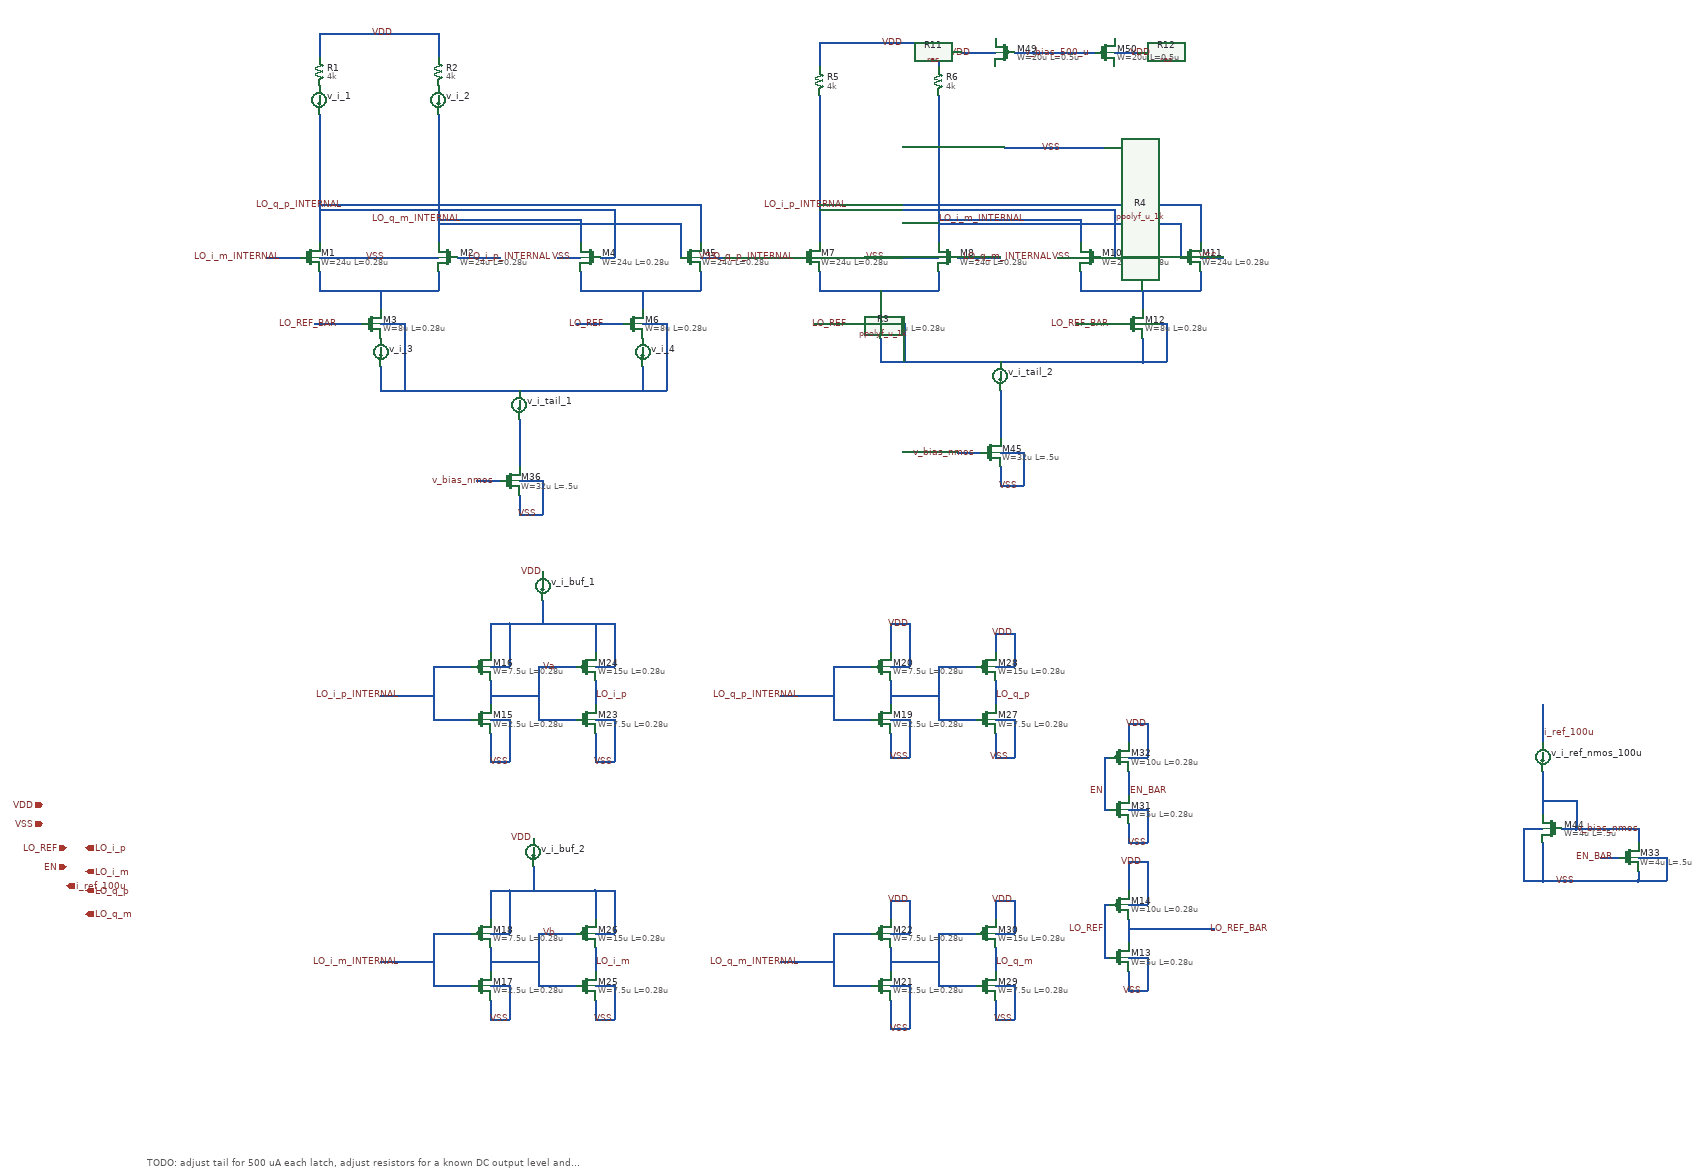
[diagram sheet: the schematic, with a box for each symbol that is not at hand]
v {xschem version=3.4.8RC file_version=1.3}
G {}
K {}
V {}
S {}
F {}
E {}
T {TODO: adjust tail for 500 uA each latch, adjust resistors for a known DC output level and swing, add latch output stage to couple into output buffer. Remove self biasing or add wideband buffer to help with low frequency clock signasl} 50 170 0 0 0.2 0.2 {}
N 410 -1690 410 -1650 {lab=#net1}
N 410 -1650 660 -1650 {lab=#net1}
N 660 -1690 660 -1650 {lab=#net1}
N 540 -1650 540 -1610 {lab=#net1}
N 400 -1580 500 -1580 {lab=LO_REF_BAR}
N 540 -1490 540 -1440 {lab=#net2}
N 300 -1720 370 -1720 {lab=LO_i_m_INTERNAL}
N 700 -1720 790 -1720 {lab=LO_i_p_INTERNAL}
N 660 -1860 660 -1750 {lab=LO_q_m_INTERNAL}
N 410 -1870 410 -1750 {lab=LO_q_p_INTERNAL}
N 410 -2190 660 -2190 {lab=VDD}
N 960 -1690 960 -1650 {lab=#net3}
N 960 -1650 1210 -1650 {lab=#net3}
N 1210 -1690 1210 -1650 {lab=#net3}
N 1090 -1650 1090 -1610 {lab=#net3}
N 950 -1580 1050 -1580 {lab=LO_REF}
N 1090 -1490 1090 -1440 {lab=#net2}
N 960 -1800 960 -1750 {lab=LO_q_m_INTERNAL}
N 1000 -1720 1030 -1720 {lab=LO_q_p_INTERNAL}
N 1030 -1770 1030 -1720 {lab=LO_q_p_INTERNAL}
N 660 -1800 960 -1800 {lab=LO_q_m_INTERNAL}
N 1030 -1820 1030 -1770 {lab=LO_q_p_INTERNAL}
N 410 -1820 1030 -1820 {lab=LO_q_p_INTERNAL}
N 1170 -1790 1170 -1720 {lab=LO_q_m_INTERNAL}
N 660 -1790 1170 -1790 {lab=LO_q_m_INTERNAL}
N 1210 -1830 1210 -1750 {lab=LO_q_p_INTERNAL}
N 410 -1830 1210 -1830 {lab=LO_q_p_INTERNAL}
N 540 -1440 1090 -1440 {lab=#net2}
N 540 -1580 590 -1580 {lab=#net2}
N 590 -1510 590 -1440 {lab=#net2}
N 590 -1580 590 -1570 {lab=#net2}
N 1090 -1580 1140 -1580 {lab=#net2}
N 1140 -1520 1140 -1440 {lab=#net2}
N 1090 -1440 1140 -1440 {lab=#net2}
N 910 -1720 960 -1720 {lab=VSS}
N 1210 -1720 1260 -1720 {lab=VSS}
N 410 -1720 660 -1720 {lab=VSS}
N 1460 -1690 1460 -1650 {lab=#net4}
N 1460 -1650 1710 -1650 {lab=#net4}
N 1710 -1690 1710 -1650 {lab=#net4}
N 1590 -1650 1590 -1610 {lab=#net4}
N 1450 -1580 1550 -1580 {lab=LO_REF}
N 1590 -1550 1590 -1500 {lab=#net5}
N 1350 -1720 1420 -1720 {lab=LO_q_p_INTERNAL}
N 1750 -1720 1840 -1720 {lab=LO_q_m_INTERNAL}
N 1710 -1860 1710 -1750 {lab=LO_i_m_INTERNAL}
N 1460 -1870 1460 -1750 {lab=LO_i_p_INTERNAL}
N 1460 -2170 1710 -2170 {lab=VDD}
N 2010 -1690 2010 -1650 {lab=#net6}
N 2010 -1650 2260 -1650 {lab=#net6}
N 2260 -1690 2260 -1650 {lab=#net6}
N 2140 -1650 2140 -1610 {lab=#net6}
N 2000 -1580 2100 -1580 {lab=LO_REF_BAR}
N 2140 -1550 2140 -1500 {lab=#net5}
N 2010 -1800 2010 -1750 {lab=LO_i_m_INTERNAL}
N 2050 -1720 2080 -1720 {lab=LO_i_p_INTERNAL}
N 2080 -1770 2080 -1720 {lab=LO_i_p_INTERNAL}
N 1710 -1800 2010 -1800 {lab=LO_i_m_INTERNAL}
N 2080 -1820 2080 -1770 {lab=LO_i_p_INTERNAL}
N 1460 -1820 2080 -1820 {lab=LO_i_p_INTERNAL}
N 2220 -1790 2220 -1720 {lab=LO_i_m_INTERNAL}
N 1710 -1790 2220 -1790 {lab=LO_i_m_INTERNAL}
N 2260 -1830 2260 -1750 {lab=LO_i_p_INTERNAL}
N 1460 -1830 2260 -1830 {lab=LO_i_p_INTERNAL}
N 1590 -1500 2140 -1500 {lab=#net5}
N 1590 -1580 1640 -1580 {lab=#net5}
N 1640 -1570 1640 -1500 {lab=#net5}
N 1640 -1580 1640 -1570 {lab=#net5}
N 2140 -1580 2190 -1580 {lab=#net5}
N 2190 -1580 2190 -1500 {lab=#net5}
N 2140 -1500 2190 -1500 {lab=#net5}
N 1960 -1720 2010 -1720 {lab=VSS}
N 2260 -1720 2310 -1720 {lab=VSS}
N 1460 -1720 1710 -1720 {lab=VSS}
N 2060 -250 2070 -250 {lab=LO_REF}
N 2060 -360 2060 -250 {lab=LO_REF}
N 2060 -360 2070 -360 {lab=LO_REF}
N 2110 -330 2110 -280 {lab=LO_REF_BAR}
N 2110 -220 2110 -180 {lab=VSS}
N 2110 -360 2150 -360 {lab=VDD}
N 2110 -250 2150 -250 {lab=VSS}
N 2150 -250 2150 -180 {lab=VSS}
N 720 -750 730 -750 {lab=LO_i_p_INTERNAL}
N 650 -860 650 -750 {lab=LO_i_p_INTERNAL}
N 720 -860 730 -860 {lab=LO_i_p_INTERNAL}
N 770 -830 770 -780 {lab=Va}
N 770 -720 770 -680 {lab=VSS}
N 770 -930 770 -890 {lab=#net7}
N 770 -860 810 -860 {lab=#net7}
N 770 -950 810 -950 {lab=#net7}
N 770 -750 810 -750 {lab=VSS}
N 810 -750 810 -680 {lab=VSS}
N 650 -750 720 -750 {lab=LO_i_p_INTERNAL}
N 650 -860 710 -860 {lab=LO_i_p_INTERNAL}
N 710 -860 720 -860 {lab=LO_i_p_INTERNAL}
N 540 -800 590 -800 {lab=LO_i_p_INTERNAL}
N 720 -190 730 -190 {lab=LO_i_m_INTERNAL}
N 650 -300 650 -190 {lab=LO_i_m_INTERNAL}
N 720 -300 730 -300 {lab=LO_i_m_INTERNAL}
N 770 -270 770 -220 {lab=Vb}
N 770 -370 770 -330 {lab=#net8}
N 770 -300 810 -300 {lab=#net8}
N 770 -190 810 -190 {lab=VSS}
N 650 -190 720 -190 {lab=LO_i_m_INTERNAL}
N 650 -300 710 -300 {lab=LO_i_m_INTERNAL}
N 710 -300 720 -300 {lab=LO_i_m_INTERNAL}
N 540 -240 590 -240 {lab=LO_i_m_INTERNAL}
N 1560 -750 1570 -750 {lab=LO_q_p_INTERNAL}
N 1490 -860 1490 -750 {lab=LO_q_p_INTERNAL}
N 1560 -860 1570 -860 {lab=LO_q_p_INTERNAL}
N 1610 -830 1610 -780 {lab=#net9}
N 1610 -720 1610 -680 {lab=VSS}
N 1610 -930 1610 -890 {lab=VDD}
N 1610 -860 1650 -860 {lab=VDD}
N 1610 -750 1650 -750 {lab=VSS}
N 1490 -750 1560 -750 {lab=LO_q_p_INTERNAL}
N 1490 -860 1550 -860 {lab=LO_q_p_INTERNAL}
N 1550 -860 1560 -860 {lab=LO_q_p_INTERNAL}
N 1380 -800 1430 -800 {lab=LO_q_p_INTERNAL}
N 1560 -190 1570 -190 {lab=LO_q_m_INTERNAL}
N 1490 -300 1490 -190 {lab=LO_q_m_INTERNAL}
N 1560 -300 1570 -300 {lab=LO_q_m_INTERNAL}
N 1610 -270 1610 -220 {lab=#net10}
N 1610 -370 1610 -330 {lab=VDD}
N 1610 -300 1650 -300 {lab=VDD}
N 1610 -190 1650 -190 {lab=VSS}
N 1490 -190 1560 -190 {lab=LO_q_m_INTERNAL}
N 1490 -300 1550 -300 {lab=LO_q_m_INTERNAL}
N 1550 -300 1560 -300 {lab=LO_q_m_INTERNAL}
N 1380 -240 1430 -240 {lab=LO_q_m_INTERNAL}
N 940 -750 950 -750 {lab=Va}
N 940 -860 950 -860 {lab=Va}
N 990 -830 990 -780 {lab=LO_i_p}
N 990 -720 990 -680 {lab=VSS}
N 990 -930 990 -890 {lab=#net7}
N 990 -860 1030 -860 {lab=#net7}
N 1030 -930 1030 -860 {lab=#net7}
N 990 -750 1030 -750 {lab=VSS}
N 870 -750 940 -750 {lab=Va}
N 870 -860 930 -860 {lab=Va}
N 930 -860 940 -860 {lab=Va}
N 870 -860 870 -750 {lab=Va}
N 770 -800 870 -800 {lab=Va}
N 940 -190 950 -190 {lab=Vb}
N 940 -300 950 -300 {lab=Vb}
N 990 -270 990 -220 {lab=LO_i_m}
N 990 -370 990 -330 {lab=#net8}
N 990 -300 1030 -300 {lab=#net8}
N 1030 -370 1030 -300 {lab=#net8}
N 990 -390 1030 -390 {lab=#net8}
N 990 -190 1030 -190 {lab=VSS}
N 870 -190 940 -190 {lab=Vb}
N 870 -300 930 -300 {lab=Vb}
N 930 -300 940 -300 {lab=Vb}
N 870 -300 870 -190 {lab=Vb}
N 770 -240 870 -240 {lab=Vb}
N 1780 -750 1790 -750 {lab=#net9}
N 1780 -860 1790 -860 {lab=#net9}
N 1830 -830 1830 -780 {lab=LO_q_p}
N 1830 -720 1830 -680 {lab=VSS}
N 1830 -930 1830 -890 {lab=VDD}
N 1830 -860 1870 -860 {lab=VDD}
N 1870 -930 1870 -860 {lab=VDD}
N 1830 -930 1870 -930 {lab=VDD}
N 1830 -750 1870 -750 {lab=VSS}
N 1710 -750 1780 -750 {lab=#net9}
N 1710 -860 1770 -860 {lab=#net9}
N 1770 -860 1780 -860 {lab=#net9}
N 1710 -860 1710 -750 {lab=#net9}
N 1610 -800 1710 -800 {lab=#net9}
N 1780 -190 1790 -190 {lab=#net10}
N 1780 -300 1790 -300 {lab=#net10}
N 1830 -270 1830 -220 {lab=LO_q_m}
N 1830 -370 1830 -330 {lab=VDD}
N 1830 -300 1870 -300 {lab=VDD}
N 1870 -370 1870 -300 {lab=VDD}
N 1830 -370 1870 -370 {lab=VDD}
N 1830 -190 1870 -190 {lab=VSS
}
N 1710 -190 1780 -190 {lab=#net10}
N 1710 -300 1770 -300 {lab=#net10}
N 1770 -300 1780 -300 {lab=#net10}
N 1710 -300 1710 -190 {lab=#net10}
N 1610 -240 1710 -240 {lab=#net10}
N 2060 -560 2070 -560 {lab=EN}
N 2060 -670 2060 -560 {lab=EN}
N 2060 -670 2070 -670 {lab=EN}
N 2110 -640 2110 -590 {lab=EN_BAR}
N 2110 -530 2110 -490 {lab=VSS}
N 2110 -740 2110 -700 {lab=VDD}
N 2110 -670 2150 -670 {lab=VDD}
N 2150 -740 2150 -670 {lab=VDD}
N 2110 -740 2150 -740 {lab=VDD}
N 2110 -560 2150 -560 {lab=VSS}
N 2150 -560 2150 -490 {lab=VSS}
N 2110 -490 2150 -490 {lab=VSS}
N 2110 -310 2280 -310 {lab=LO_REF_BAR}
N 2280 -310 2290 -310 {lab=LO_REF_BAR}
N 770 -680 770 -660 {lab=VSS}
N 1030 -750 1030 -680 {lab=VSS}
N 1030 -190 1030 -140 {lab=VSS}
N 810 -190 810 -140 {lab=VSS}
N 1460 -2000 1460 -1930 {lab=LO_i_p_INTERNAL}
N 1870 -190 1870 -140 {lab=VSS}
N 1650 -740 1650 -700 {lab=VSS}
N 1650 -750 1650 -740 {lab=VSS}
N 1870 -750 1870 -700 {lab=VSS}
N 410 -1970 410 -1930 {lab=LO_q_p_INTERNAL}
N 660 -1870 660 -1860 {lab=LO_q_m_INTERNAL}
N 660 -1970 660 -1930 {lab=LO_q_m_INTERNAL}
N 1850 -1950 2060 -1950 {lab=VSS
spice_ignore=true}
N 1710 -1870 1710 -1860 {lab=LO_i_m_INTERNAL}
N 1710 -1940 1710 -1870 {lab=LO_i_m_INTERNAL}
N 1460 -2060 1460 -2000 {lab=LO_i_p_INTERNAL}
N 1710 -2060 1710 -2000 {lab=LO_i_m_INTERNAL}
N 810 -680 810 -660 {lab=VSS}
N 1030 -680 1030 -660 {lab=VSS}
N 990 -660 1030 -660 {lab=VSS}
N 990 -680 990 -660 {lab=VSS}
N 770 -160 770 -130 {lab=VSS}
N 770 -130 770 -120 {lab=VSS}
N 810 -140 810 -120 {lab=VSS}
N 990 -160 990 -130 {lab=VSS}
N 990 -130 990 -120 {lab=VSS}
N 990 -120 1030 -120 {lab=VSS}
N 1030 -140 1030 -120 {lab=VSS}
N 1610 -680 1610 -670 {lab=VSS}
N 1650 -700 1650 -670 {lab=VSS}
N 1830 -680 1830 -670 {lab=VSS}
N 1830 -670 1870 -670 {lab=VSS}
N 1870 -700 1870 -670 {lab=VSS}
N 1610 -160 1610 -120 {lab=VSS}
N 1830 -160 1830 -120 {lab=VSS}
N 1830 -120 1870 -120 {lab=VSS}
N 1870 -140 1870 -120 {lab=VSS}
N 770 -950 770 -930 {lab=#net7}
N 1610 -950 1650 -950 {lab=VDD}
N 1610 -950 1610 -930 {lab=VDD}
N 770 -390 810 -390 {lab=#net8}
N 770 -390 770 -370 {lab=#net8}
N 1610 -370 1650 -370 {lab=VDD}
N 1610 -120 1610 -100 {lab=VSS}
N 1650 -190 1650 -100 {lab=VSS}
N 1650 -370 1650 -300 {lab=VDD}
N 1650 -950 1650 -860 {lab=VDD}
N 810 -950 810 -860 {lab=#net7}
N 810 -390 810 -300 {lab=#net8}
N 590 -800 650 -800 {lab=LO_i_p_INTERNAL}
N 590 -240 650 -240 {lab=LO_i_m_INTERNAL}
N 2980 -640 2980 -550 {lab=v_bias_nmos
}
N 2980 -490 2980 -450 {lab=VSS
}
N 1840 -1280 1840 -1240 {lab=VSS
}
N 1840 -1240 1890 -1240 {lab=VSS
}
N 1890 -1310 1890 -1240 {lab=VSS
}
N 1840 -1310 1890 -1310 {lab=VSS
}
N 410 -2020 410 -1970 {lab=LO_q_p_INTERNAL}
N 660 -2020 660 -1970 {lab=LO_q_m_INTERNAL}
N 410 -2190 410 -2140 {lab=VDD}
N 660 -2190 660 -2140 {lab=VDD}
N 1460 -2170 1460 -2120 {lab=VDD}
N 1760 -2150 1830 -2150 {lab=VDD
spice_ignore=true}
N 1880 -2150 2040 -2150 {lab=v_bias_500_u
spice_ignore=true}
N 1870 -2150 1880 -2150 {lab=v_bias_500_u
spice_ignore=true}
N 2080 -2150 2130 -2150 {lab=VDD
spice_ignore=true}
N 1710 -2170 1710 -2120 {lab=VDD}
N 2940 -520 2980 -520 {lab=VSS}
N 2940 -520 2940 -450 {lab=VSS}
N 2940 -410 2980 -410 {lab=VSS}
N 1460 -1930 1460 -1870 {lab=LO_i_p_INTERNAL}
N 1710 -2000 1710 -1940 {lab=LO_i_m_INTERNAL}
N 660 -1930 660 -1870 {lab=LO_q_m_INTERNAL}
N 410 -1930 410 -1870 {lab=LO_q_p_INTERNAL}
N 2980 -750 2980 -700 {lab=i_ref_100u}
N 3020 -520 3050 -520 {lab=v_bias_nmos}
N 3050 -580 3050 -520 {lab=v_bias_nmos}
N 2980 -580 3050 -580 {lab=v_bias_nmos}
N 2980 -780 2980 -750 {lab=i_ref_100u}
N 1140 -1580 1140 -1520 {lab=#net2}
N 590 -1570 590 -1510 {lab=#net2}
N 770 -660 810 -660 {lab=VSS}
N 770 -120 810 -120 {lab=VSS}
N 1430 -800 1490 -800 {lab=LO_q_p_INTERNAL}
N 1430 -240 1490 -240 {lab=LO_q_m_INTERNAL}
N 1610 -670 1640 -670 {lab=VSS}
N 1640 -670 1650 -670 {lab=VSS}
N 1610 -100 1650 -100 {lab=VSS}
N 810 -950 1020 -950 {lab=#net7}
N 1020 -950 1030 -950 {lab=#net7}
N 990 -950 990 -930 {lab=#net7}
N 1030 -950 1030 -930 {lab=#net7}
N 880 -1000 880 -960 {lab=#net7}
N 880 -960 880 -950 {lab=#net7}
N 860 -440 860 -400 {lab=#net8}
N 860 -400 860 -390 {lab=#net8}
N 1030 -390 1030 -380 {lab=#net8}
N 990 -390 990 -380 {lab=#net8}
N 810 -390 990 -390 {lab=#net8}
N 990 -380 990 -370 {lab=#net8}
N 1030 -380 1030 -370 {lab=#net8}
N 1750 -1310 1800 -1310 {lab=v_bias_nmos}
N 1840 -1440 1840 -1340 {lab=#net11}
N 830 -1220 830 -1180 {lab=VSS
}
N 830 -1180 880 -1180 {lab=VSS
}
N 880 -1250 880 -1180 {lab=VSS
}
N 830 -1250 880 -1250 {lab=VSS
}
N 740 -1250 790 -1250 {lab=v_bias_nmos}
N 830 -1380 830 -1280 {lab=#net12}
N 3050 -520 3180 -520 {lab=v_bias_nmos}
N 2110 -450 2110 -390 {lab=VDD}
N 2150 -450 2150 -360 {lab=VDD}
N 2120 -450 2150 -450 {lab=VDD}
N 2110 -450 2120 -450 {lab=VDD}
N 2110 -180 2150 -180 {lab=VSS}
N 3100 -460 3140 -460 {lab=EN_BAR}
N 3180 -460 3240 -460 {lab=VSS}
N 3240 -460 3240 -410 {lab=VSS}
N 3180 -410 3240 -410 {lab=VSS}
N 3180 -430 3180 -410 {lab=VSS}
N 2980 -410 3180 -410 {lab=VSS}
N 2980 -450 2980 -410 {lab=VSS}
N 2940 -450 2940 -410 {lab=VSS}
N 3180 -520 3180 -490 {lab=v_bias_nmos}
C {title.sym} 160 110 0 0 {name=LO Divider author="Lei Chen"}
C {symbols/nfet_03v3.sym} 390 -1720 0 0 {name=M1
L=0.28u
W=24u
nf=6
m=1
ad="'int((nf+1)/2) * W/nf * 0.18u'"
pd="'2*int((nf+1)/2) * (W/nf + 0.18u)'"
as="'int((nf+2)/2) * W/nf * 0.18u'"
ps="'2*int((nf+2)/2) * (W/nf + 0.18u)'"
nrd="'0.18u / W'" nrs="'0.18u / W'"
sa=0 sb=0 sd=0
model=nfet_03v3
spiceprefix=X
}
C {symbols/nfet_03v3.sym} 680 -1720 0 1 {name=M2
L=0.28u
W=24u
nf=6
m=1
ad="'int((nf+1)/2) * W/nf * 0.18u'"
pd="'2*int((nf+1)/2) * (W/nf + 0.18u)'"
as="'int((nf+2)/2) * W/nf * 0.18u'"
ps="'2*int((nf+2)/2) * (W/nf + 0.18u)'"
nrd="'0.18u / W'" nrs="'0.18u / W'"
sa=0 sb=0 sd=0
model=nfet_03v3
spiceprefix=X
}
C {symbols/nfet_03v3.sym} 520 -1580 0 0 {name=M3
L=0.28u
W=8u
nf=2
m=1
ad="'int((nf+1)/2) * W/nf * 0.18u'"
pd="'2*int((nf+1)/2) * (W/nf + 0.18u)'"
as="'int((nf+2)/2) * W/nf * 0.18u'"
ps="'2*int((nf+2)/2) * (W/nf + 0.18u)'"
nrd="'0.18u / W'" nrs="'0.18u / W'"
sa=0 sb=0 sd=0
model=nfet_03v3
spiceprefix=X
}
C {symbols/nfet_03v3.sym} 980 -1720 0 1 {name=M4
L=0.28u
W=24u
nf=6
m=1
ad="'int((nf+1)/2) * W/nf * 0.18u'"
pd="'2*int((nf+1)/2) * (W/nf + 0.18u)'"
as="'int((nf+2)/2) * W/nf * 0.18u'"
ps="'2*int((nf+2)/2) * (W/nf + 0.18u)'"
nrd="'0.18u / W'" nrs="'0.18u / W'"
sa=0 sb=0 sd=0
model=nfet_03v3
spiceprefix=X
}
C {symbols/nfet_03v3.sym} 1190 -1720 0 0 {name=M5
L=0.28u
W=24u
nf=6
m=1
ad="'int((nf+1)/2) * W/nf * 0.18u'"
pd="'2*int((nf+1)/2) * (W/nf + 0.18u)'"
as="'int((nf+2)/2) * W/nf * 0.18u'"
ps="'2*int((nf+2)/2) * (W/nf + 0.18u)'"
nrd="'0.18u / W'" nrs="'0.18u / W'"
sa=0 sb=0 sd=0
model=nfet_03v3
spiceprefix=X
}
C {symbols/nfet_03v3.sym} 1070 -1580 0 0 {name=M6
L=0.28u
W=8u
nf=2
m=1
ad="'int((nf+1)/2) * W/nf * 0.18u'"
pd="'2*int((nf+1)/2) * (W/nf + 0.18u)'"
as="'int((nf+2)/2) * W/nf * 0.18u'"
ps="'2*int((nf+2)/2) * (W/nf + 0.18u)'"
nrd="'0.18u / W'" nrs="'0.18u / W'"
sa=0 sb=0 sd=0
model=nfet_03v3
spiceprefix=X
}
C {iopin.sym} -170 -570 0 0 {name=p1 lab=VDD}
C {iopin.sym} -170 -530 0 0 {name=p2 lab=VSS}
C {ipin.sym} -120 -480 0 0 {name=p3 lab=LO_REF}
C {opin.sym} -80 -480 0 0 {name=p5 lab=LO_i_p}
C {opin.sym} -80 -430 0 0 {name=p6 lab=LO_i_m}
C {lab_wire.sym} 450 -1580 0 0 {name=p8 sig_type=std_logic lab=LO_REF_BAR}
C {lab_wire.sym} 550 -1720 0 0 {name=p12 sig_type=std_logic lab=VSS}
C {lab_wire.sym} 940 -1720 0 0 {name=p16 sig_type=std_logic lab=VSS}
C {lab_wire.sym} 1250 -1720 0 0 {name=p17 sig_type=std_logic lab=VSS}
C {symbols/nfet_03v3.sym} 1440 -1720 0 0 {name=M7
L=0.28u
W=24u
nf=6
m=1
ad="'int((nf+1)/2) * W/nf * 0.18u'"
pd="'2*int((nf+1)/2) * (W/nf + 0.18u)'"
as="'int((nf+2)/2) * W/nf * 0.18u'"
ps="'2*int((nf+2)/2) * (W/nf + 0.18u)'"
nrd="'0.18u / W'" nrs="'0.18u / W'"
sa=0 sb=0 sd=0
model=nfet_03v3
spiceprefix=X
}
C {symbols/nfet_03v3.sym} 1730 -1720 0 1 {name=M8
L=0.28u
W=24u
nf=6
m=1
ad="'int((nf+1)/2) * W/nf * 0.18u'"
pd="'2*int((nf+1)/2) * (W/nf + 0.18u)'"
as="'int((nf+2)/2) * W/nf * 0.18u'"
ps="'2*int((nf+2)/2) * (W/nf + 0.18u)'"
nrd="'0.18u / W'" nrs="'0.18u / W'"
sa=0 sb=0 sd=0
model=nfet_03v3
spiceprefix=X
}
C {symbols/nfet_03v3.sym} 1570 -1580 0 0 {name=M9
L=0.28u
W=8u
nf=2
m=1
ad="'int((nf+1)/2) * W/nf * 0.18u'"
pd="'2*int((nf+1)/2) * (W/nf + 0.18u)'"
as="'int((nf+2)/2) * W/nf * 0.18u'"
ps="'2*int((nf+2)/2) * (W/nf + 0.18u)'"
nrd="'0.18u / W'" nrs="'0.18u / W'"
sa=0 sb=0 sd=0
model=nfet_03v3
spiceprefix=X
}
C {symbols/nfet_03v3.sym} 2030 -1720 0 1 {name=M10
L=0.28u
W=24u
nf=6
m=1
ad="'int((nf+1)/2) * W/nf * 0.18u'"
pd="'2*int((nf+1)/2) * (W/nf + 0.18u)'"
as="'int((nf+2)/2) * W/nf * 0.18u'"
ps="'2*int((nf+2)/2) * (W/nf + 0.18u)'"
nrd="'0.18u / W'" nrs="'0.18u / W'"
sa=0 sb=0 sd=0
model=nfet_03v3
spiceprefix=X
}
C {symbols/nfet_03v3.sym} 2240 -1720 0 0 {name=M11
L=0.28u
W=24u
nf=6
m=1
ad="'int((nf+1)/2) * W/nf * 0.18u'"
pd="'2*int((nf+1)/2) * (W/nf + 0.18u)'"
as="'int((nf+2)/2) * W/nf * 0.18u'"
ps="'2*int((nf+2)/2) * (W/nf + 0.18u)'"
nrd="'0.18u / W'" nrs="'0.18u / W'"
sa=0 sb=0 sd=0
model=nfet_03v3
spiceprefix=X
}
C {symbols/nfet_03v3.sym} 2120 -1580 0 0 {name=M12
L=0.28u
W=8u
nf=2
m=1
ad="'int((nf+1)/2) * W/nf * 0.18u'"
pd="'2*int((nf+1)/2) * (W/nf + 0.18u)'"
as="'int((nf+2)/2) * W/nf * 0.18u'"
ps="'2*int((nf+2)/2) * (W/nf + 0.18u)'"
nrd="'0.18u / W'" nrs="'0.18u / W'"
sa=0 sb=0 sd=0
model=nfet_03v3
spiceprefix=X
}
C {lab_wire.sym} 1880 -1240 0 0 {name=p18 sig_type=std_logic lab=VSS}
C {lab_wire.sym} 2070 -1580 0 0 {name=p20 sig_type=std_logic lab=LO_REF_BAR}
C {lab_wire.sym} 1600 -1720 0 0 {name=p23 sig_type=std_logic lab=VSS}
C {lab_wire.sym} 1780 -2150 0 0 {name=p26 sig_type=std_logic lab=VDD
spice_ignore=true}
C {lab_wire.sym} 1990 -1720 0 0 {name=p27 sig_type=std_logic lab=VSS}
C {lab_wire.sym} 2300 -1720 0 0 {name=p28 sig_type=std_logic lab=VSS}
C {opin.sym} -80 -390 0 0 {name=p29 lab=LO_q_p}
C {opin.sym} -80 -340 0 0 {name=p30 lab=LO_q_m}
C {symbols/nfet_03v3.sym} 2090 -250 0 0 {name=M13
L=0.28u
W=5u
nf=1
m=1
ad="'int((nf+1)/2) * W/nf * 0.18u'"
pd="'2*int((nf+1)/2) * (W/nf + 0.18u)'"
as="'int((nf+2)/2) * W/nf * 0.18u'"
ps="'2*int((nf+2)/2) * (W/nf + 0.18u)'"
nrd="'0.18u / W'" nrs="'0.18u / W'"
sa=0 sb=0 sd=0
model=nfet_03v3
spiceprefix=X
}
C {symbols/pfet_03v3.sym} 2090 -360 0 0 {name=M14
L=0.28u
W=10u
nf=1
m=1
ad="'int((nf+1)/2) * W/nf * 0.18u'"
pd="'2*int((nf+1)/2) * (W/nf + 0.18u)'"
as="'int((nf+2)/2) * W/nf * 0.18u'"
ps="'2*int((nf+2)/2) * (W/nf + 0.18u)'"
nrd="'0.18u / W'" nrs="'0.18u / W'"
sa=0 sb=0 sd=0
model=pfet_03v3
spiceprefix=X
}
C {lab_wire.sym} 2280 -310 0 1 {name=p33 sig_type=std_logic lab=LO_REF_BAR}
C {symbols/nfet_03v3.sym} 750 -750 0 0 {name=M15
L=0.28u
W=2.5u
nf=1
m=1
ad="'int((nf+1)/2) * W/nf * 0.18u'"
pd="'2*int((nf+1)/2) * (W/nf + 0.18u)'"
as="'int((nf+2)/2) * W/nf * 0.18u'"
ps="'2*int((nf+2)/2) * (W/nf + 0.18u)'"
nrd="'0.18u / W'" nrs="'0.18u / W'"
sa=0 sb=0 sd=0
model=nfet_03v3
spiceprefix=X
}
C {symbols/pfet_03v3.sym} 750 -860 0 0 {name=M16
L=0.28u
W=7.5u
nf=3
m=1
ad="'int((nf+1)/2) * W/nf * 0.18u'"
pd="'2*int((nf+1)/2) * (W/nf + 0.18u)'"
as="'int((nf+2)/2) * W/nf * 0.18u'"
ps="'2*int((nf+2)/2) * (W/nf + 0.18u)'"
nrd="'0.18u / W'" nrs="'0.18u / W'"
sa=0 sb=0 sd=0
model=pfet_03v3
spiceprefix=X
}
C {lab_wire.sym} 880 -1060 0 0 {name=p34 sig_type=std_logic lab=VDD}
C {lab_wire.sym} 580 -800 0 0 {name=p36 sig_type=std_logic lab=LO_i_p_INTERNAL}
C {symbols/nfet_03v3.sym} 750 -190 0 0 {name=M17
L=0.28u
W=2.5u
nf=1
m=1
ad="'int((nf+1)/2) * W/nf * 0.18u'"
pd="'2*int((nf+1)/2) * (W/nf + 0.18u)'"
as="'int((nf+2)/2) * W/nf * 0.18u'"
ps="'2*int((nf+2)/2) * (W/nf + 0.18u)'"
nrd="'0.18u / W'" nrs="'0.18u / W'"
sa=0 sb=0 sd=0
model=nfet_03v3
spiceprefix=X
}
C {symbols/pfet_03v3.sym} 750 -300 0 0 {name=M18
L=0.28u
W=7.5u
nf=3
m=1
ad="'int((nf+1)/2) * W/nf * 0.18u'"
pd="'2*int((nf+1)/2) * (W/nf + 0.18u)'"
as="'int((nf+2)/2) * W/nf * 0.18u'"
ps="'2*int((nf+2)/2) * (W/nf + 0.18u)'"
nrd="'0.18u / W'" nrs="'0.18u / W'"
sa=0 sb=0 sd=0
model=pfet_03v3
spiceprefix=X
}
C {lab_wire.sym} 580 -240 0 0 {name=p39 sig_type=std_logic lab=LO_i_m_INTERNAL}
C {symbols/nfet_03v3.sym} 1590 -750 0 0 {name=M19
L=0.28u
W=2.5u
nf=1
m=1
ad="'int((nf+1)/2) * W/nf * 0.18u'"
pd="'2*int((nf+1)/2) * (W/nf + 0.18u)'"
as="'int((nf+2)/2) * W/nf * 0.18u'"
ps="'2*int((nf+2)/2) * (W/nf + 0.18u)'"
nrd="'0.18u / W'" nrs="'0.18u / W'"
sa=0 sb=0 sd=0
model=nfet_03v3
spiceprefix=X
}
C {symbols/pfet_03v3.sym} 1590 -860 0 0 {name=M20
L=0.28u
W=7.5u
nf=3
m=1
ad="'int((nf+1)/2) * W/nf * 0.18u'"
pd="'2*int((nf+1)/2) * (W/nf + 0.18u)'"
as="'int((nf+2)/2) * W/nf * 0.18u'"
ps="'2*int((nf+2)/2) * (W/nf + 0.18u)'"
nrd="'0.18u / W'" nrs="'0.18u / W'"
sa=0 sb=0 sd=0
model=pfet_03v3
spiceprefix=X
}
C {lab_wire.sym} 1420 -800 0 0 {name=p44 sig_type=std_logic lab=LO_q_p_INTERNAL}
C {symbols/nfet_03v3.sym} 1590 -190 0 0 {name=M21
L=0.28u
W=2.5u
nf=1
m=1
ad="'int((nf+1)/2) * W/nf * 0.18u'"
pd="'2*int((nf+1)/2) * (W/nf + 0.18u)'"
as="'int((nf+2)/2) * W/nf * 0.18u'"
ps="'2*int((nf+2)/2) * (W/nf + 0.18u)'"
nrd="'0.18u / W'" nrs="'0.18u / W'"
sa=0 sb=0 sd=0
model=nfet_03v3
spiceprefix=X
}
C {symbols/pfet_03v3.sym} 1590 -300 0 0 {name=M22
L=0.28u
W=7.5u
nf=3
m=1
ad="'int((nf+1)/2) * W/nf * 0.18u'"
pd="'2*int((nf+1)/2) * (W/nf + 0.18u)'"
as="'int((nf+2)/2) * W/nf * 0.18u'"
ps="'2*int((nf+2)/2) * (W/nf + 0.18u)'"
nrd="'0.18u / W'" nrs="'0.18u / W'"
sa=0 sb=0 sd=0
model=pfet_03v3
spiceprefix=X
}
C {lab_wire.sym} 1420 -240 0 0 {name=p47 sig_type=std_logic lab=LO_q_m_INTERNAL}
C {symbols/pfet_03v3.sym} 970 -860 0 0 {name=M24
L=0.28u
W=15u
nf=6
m=1
ad="'int((nf+1)/2) * W/nf * 0.18u'"
pd="'2*int((nf+1)/2) * (W/nf + 0.18u)'"
as="'int((nf+2)/2) * W/nf * 0.18u'"
ps="'2*int((nf+2)/2) * (W/nf + 0.18u)'"
nrd="'0.18u / W'" nrs="'0.18u / W'"
sa=0 sb=0 sd=0
model=pfet_03v3
spiceprefix=X
}
C {lab_wire.sym} 990 -800 0 1 {name=p48 sig_type=std_logic lab=LO_i_p}
C {symbols/pfet_03v3.sym} 970 -300 0 0 {name=M26
L=0.28u
W=15u
nf=6
m=1
ad="'int((nf+1)/2) * W/nf * 0.18u'"
pd="'2*int((nf+1)/2) * (W/nf + 0.18u)'"
as="'int((nf+2)/2) * W/nf * 0.18u'"
ps="'2*int((nf+2)/2) * (W/nf + 0.18u)'"
nrd="'0.18u / W'" nrs="'0.18u / W'"
sa=0 sb=0 sd=0
model=pfet_03v3
spiceprefix=X
}
C {lab_wire.sym} 990 -240 0 1 {name=p51 sig_type=std_logic lab=LO_i_m}
C {symbols/pfet_03v3.sym} 1810 -860 0 0 {name=M28
L=0.28u
W=15u
nf=6
m=1
ad="'int((nf+1)/2) * W/nf * 0.18u'"
pd="'2*int((nf+1)/2) * (W/nf + 0.18u)'"
as="'int((nf+2)/2) * W/nf * 0.18u'"
ps="'2*int((nf+2)/2) * (W/nf + 0.18u)'"
nrd="'0.18u / W'" nrs="'0.18u / W'"
sa=0 sb=0 sd=0
model=pfet_03v3
spiceprefix=X
}
C {lab_wire.sym} 1870 -930 0 0 {name=p52 sig_type=std_logic lab=VDD}
C {lab_wire.sym} 1830 -800 0 1 {name=p54 sig_type=std_logic lab=LO_q_p}
C {symbols/pfet_03v3.sym} 1810 -300 0 0 {name=M30
L=0.28u
W=15u
nf=6
m=1
ad="'int((nf+1)/2) * W/nf * 0.18u'"
pd="'2*int((nf+1)/2) * (W/nf + 0.18u)'"
as="'int((nf+2)/2) * W/nf * 0.18u'"
ps="'2*int((nf+2)/2) * (W/nf + 0.18u)'"
nrd="'0.18u / W'" nrs="'0.18u / W'"
sa=0 sb=0 sd=0
model=pfet_03v3
spiceprefix=X
}
C {lab_wire.sym} 1870 -370 0 0 {name=p55 sig_type=std_logic lab=VDD}
C {lab_wire.sym} 1830 -240 0 1 {name=p56 sig_type=std_logic lab=LO_q_m}
C {ipin.sym} -120 -440 0 0 {name=p58 lab=EN}
C {symbols/nfet_03v3.sym} 2090 -560 0 0 {name=M31
L=0.28u
W=5u
nf=1
m=1
ad="'int((nf+1)/2) * W/nf * 0.18u'"
pd="'2*int((nf+1)/2) * (W/nf + 0.18u)'"
as="'int((nf+2)/2) * W/nf * 0.18u'"
ps="'2*int((nf+2)/2) * (W/nf + 0.18u)'"
nrd="'0.18u / W'" nrs="'0.18u / W'"
sa=0 sb=0 sd=0
model=nfet_03v3
spiceprefix=X
}
C {symbols/pfet_03v3.sym} 2090 -670 0 0 {name=M32
L=0.28u
W=10u
nf=1
m=1
ad="'int((nf+1)/2) * W/nf * 0.18u'"
pd="'2*int((nf+1)/2) * (W/nf + 0.18u)'"
as="'int((nf+2)/2) * W/nf * 0.18u'"
ps="'2*int((nf+2)/2) * (W/nf + 0.18u)'"
nrd="'0.18u / W'" nrs="'0.18u / W'"
sa=0 sb=0 sd=0
model=pfet_03v3
spiceprefix=X
}
C {lab_wire.sym} 2150 -740 0 0 {name=p59 sig_type=std_logic lab=VDD}
C {lab_wire.sym} 2150 -490 0 0 {name=p60 sig_type=std_logic lab=VSS}
C {lab_wire.sym} 2060 -600 0 0 {name=p61 sig_type=std_logic lab=EN}
C {lab_wire.sym} 2110 -600 0 1 {name=p62 sig_type=std_logic lab=EN_BAR}
C {symbols/ppolyf_u_1k.sym} 1830 -1950 0 1 {name=R3
W=1e-6
L=1.8e-6
model=ppolyf_u_1k
spiceprefix=X
m=1
spice_ignore=true}
C {symbols/ppolyf_u_1k.sym} 2080 -1950 0 0 {name=R4
W=1e-6
L=1.8e-6
model=ppolyf_u_1k
spiceprefix=X
m=1
spice_ignore=true}
C {lab_wire.sym} 1970 -1950 0 0 {name=p83 sig_type=std_logic lab=VSS
spice_ignore=true}
C {lab_wire.sym} 330 -1720 0 0 {name=p10 sig_type=std_logic lab=LO_i_m_INTERNAL}
C {lab_wire.sym} 720 -1720 0 1 {name=p11 sig_type=std_logic lab=LO_i_p_INTERNAL}
C {lab_wire.sym} 460 -1830 0 0 {name=p13 sig_type=std_logic lab=LO_q_p_INTERNAL}
C {lab_wire.sym} 710 -1800 0 0 {name=p88 sig_type=std_logic lab=LO_q_m_INTERNAL}
C {lab_wire.sym} 1410 -1720 0 0 {name=p14 sig_type=std_logic lab=LO_q_p_INTERNAL}
C {lab_wire.sym} 1760 -1720 0 1 {name=p21 sig_type=std_logic lab=LO_q_m_INTERNAL}
C {lab_wire.sym} 1520 -1830 0 0 {name=p22 sig_type=std_logic lab=LO_i_p_INTERNAL}
C {lab_wire.sym} 1710 -1800 0 1 {name=p24 sig_type=std_logic lab=LO_i_m_INTERNAL}
C {lab_wire.sym} 1030 -660 0 0 {name=p38 sig_type=std_logic lab=VSS}
C {lab_wire.sym} 1030 -120 0 0 {name=p50 sig_type=std_logic lab=VSS}
C {lab_wire.sym} 1860 -670 0 0 {name=p46 sig_type=std_logic lab=VSS}
C {lab_wire.sym} 1870 -120 0 0 {name=p57 sig_type=std_logic lab=VSS}
C {symbols/nfet_03v3.sym} 970 -750 0 0 {name=M23
L=0.28u
W=7.5u
nf=3
m=1
ad="'int((nf+1)/2) * W/nf * 0.18u'"
pd="'2*int((nf+1)/2) * (W/nf + 0.18u)'"
as="'int((nf+2)/2) * W/nf * 0.18u'"
ps="'2*int((nf+2)/2) * (W/nf + 0.18u)'"
nrd="'0.18u / W'" nrs="'0.18u / W'"
sa=0 sb=0 sd=0
model=nfet_03v3
spiceprefix=X
}
C {symbols/nfet_03v3.sym} 970 -190 0 0 {name=M25
L=0.28u
W=7.5u
nf=3
m=1
ad="'int((nf+1)/2) * W/nf * 0.18u'"
pd="'2*int((nf+1)/2) * (W/nf + 0.18u)'"
as="'int((nf+2)/2) * W/nf * 0.18u'"
ps="'2*int((nf+2)/2) * (W/nf + 0.18u)'"
nrd="'0.18u / W'" nrs="'0.18u / W'"
sa=0 sb=0 sd=0
model=nfet_03v3
spiceprefix=X
}
C {symbols/nfet_03v3.sym} 1810 -750 0 0 {name=M27
L=0.28u
W=7.5u
nf=3
m=1
ad="'int((nf+1)/2) * W/nf * 0.18u'"
pd="'2*int((nf+1)/2) * (W/nf + 0.18u)'"
as="'int((nf+2)/2) * W/nf * 0.18u'"
ps="'2*int((nf+2)/2) * (W/nf + 0.18u)'"
nrd="'0.18u / W'" nrs="'0.18u / W'"
sa=0 sb=0 sd=0
model=nfet_03v3
spiceprefix=X
}
C {symbols/nfet_03v3.sym} 1810 -190 0 0 {name=M29
L=0.28u
W=7.5u
nf=3
m=1
ad="'int((nf+1)/2) * W/nf * 0.18u'"
pd="'2*int((nf+1)/2) * (W/nf + 0.18u)'"
as="'int((nf+2)/2) * W/nf * 0.18u'"
ps="'2*int((nf+2)/2) * (W/nf + 0.18u)'"
nrd="'0.18u / W'" nrs="'0.18u / W'"
sa=0 sb=0 sd=0
model=nfet_03v3
spiceprefix=X
}
C {lab_wire.sym} 1650 -950 0 0 {name=p92 sig_type=std_logic lab=VDD}
C {lab_wire.sym} 1650 -370 0 0 {name=p42 sig_type=std_logic lab=VDD}
C {lab_wire.sym} 910 -300 0 0 {name=p77 sig_type=std_logic lab=Vb}
C {iopin.sym} -120 -400 0 1 {name=p78 lab=i_ref_100u
}
C {symbols/nfet_03v3.sym} 3000 -520 0 1 {name=M44
L=.5u
W=4u
nf=1
m=1
ad="'int((nf+1)/2) * W/nf * 0.18u'"
pd="'2*int((nf+1)/2) * (W/nf + 0.18u)'"
as="'int((nf+2)/2) * W/nf * 0.18u'"
ps="'2*int((nf+2)/2) * (W/nf + 0.18u)'"
nrd="'0.18u / W'" nrs="'0.18u / W'"
sa=0 sb=0 sd=0
model=nfet_03v3
spiceprefix=X
}
C {lab_wire.sym} 2980 -720 0 1 {name=p79 sig_type=std_logic lab=i_ref_100u
}
C {symbols/nfet_03v3.sym} 1820 -1310 0 0 {name=M45
L=.5u
W=32u
nf=8
m=1
ad="'int((nf+1)/2) * W/nf * 0.18u'"
pd="'2*int((nf+1)/2) * (W/nf + 0.18u)'"
as="'int((nf+2)/2) * W/nf * 0.18u'"
ps="'2*int((nf+2)/2) * (W/nf + 0.18u)'"
nrd="'0.18u / W'" nrs="'0.18u / W'"
sa=0 sb=0 sd=0
model=nfet_03v3
spiceprefix=X
}
C {res.sym} 1830 -2040 0 0 {name=R11
value=2k
footprint=1206
device=resistor
m=1
spice_ignore=true}
C {res.sym} 2080 -2040 0 0 {name=R12
value=2k
footprint=1206
device=resistor
m=1
spice_ignore=true}
C {symbols/pfet_03v3.sym} 1850 -2150 0 1 {name=M49
L=0.5u
W=20u
nf=5
m=1
ad="'int((nf+1)/2) * W/nf * 0.18u'"
pd="'2*int((nf+1)/2) * (W/nf + 0.18u)'"
as="'int((nf+2)/2) * W/nf * 0.18u'"
ps="'2*int((nf+2)/2) * (W/nf + 0.18u)'"
nrd="'0.18u / W'" nrs="'0.18u / W'"
sa=0 sb=0 sd=0
model=pfet_03v3
spiceprefix=X
spice_ignore=true}
C {symbols/pfet_03v3.sym} 2060 -2150 0 0 {name=M50
L=0.5u
W=20u
nf=5
m=1
ad="'int((nf+1)/2) * W/nf * 0.18u'"
pd="'2*int((nf+1)/2) * (W/nf + 0.18u)'"
as="'int((nf+2)/2) * W/nf * 0.18u'"
ps="'2*int((nf+2)/2) * (W/nf + 0.18u)'"
nrd="'0.18u / W'" nrs="'0.18u / W'"
sa=0 sb=0 sd=0
model=pfet_03v3
spiceprefix=X
spice_ignore=true}
C {lab_wire.sym} 1890 -2150 0 1 {name=p90 sig_type=std_logic lab=v_bias_500_u
spice_ignore=true}
C {lab_wire.sym} 3050 -410 0 0 {name=p91 sig_type=std_logic lab=VSS}
C {ammeter.sym} 2980 -670 0 0 {name=v_i_ref_nmos_100u savecurrent=true spice_ignore=0}
C {lab_wire.sym} 3050 -520 0 1 {name=p93 sig_type=std_logic lab=v_bias_nmos
}
C {ammeter.sym} 540 -1520 0 0 {name=v_i_3 savecurrent=true spice_ignore=0}
C {ammeter.sym} 1090 -1520 0 0 {name=v_i_4 savecurrent=true spice_ignore=0}
C {lab_wire.sym} 810 -660 0 0 {name=p25 sig_type=std_logic lab=VSS}
C {lab_wire.sym} 810 -120 0 0 {name=p35 sig_type=std_logic lab=VSS}
C {lab_wire.sym} 1650 -670 0 0 {name=p41 sig_type=std_logic lab=VSS}
C {lab_wire.sym} 1650 -100 0 0 {name=p43 sig_type=std_logic lab=VSS}
C {lab_wire.sym} 520 -2190 0 1 {name=p71 sig_type=std_logic lab=VDD}
C {lab_wire.sym} 2110 -2150 0 1 {name=p72 sig_type=std_logic lab=VDD
spice_ignore=true}
C {lab_wire.sym} 1590 -2170 0 1 {name=p76 sig_type=std_logic lab=VDD}
C {res.sym} 410 -2110 0 0 {name=R1
value=4k
footprint=1206
device=resistor
m=1}
C {res.sym} 660 -2110 0 0 {name=R2
value=4k
footprint=1206
device=resistor
m=1}
C {res.sym} 1460 -2090 0 0 {name=R5
value=4k
footprint=1206
device=resistor
m=1}
C {res.sym} 1710 -2090 0 0 {name=R6
value=4k
footprint=1206
device=resistor
m=1}
C {ammeter.sym} 410 -2050 0 0 {name=v_i_1 savecurrent=true spice_ignore=0}
C {ammeter.sym} 660 -2050 0 0 {name=v_i_2 savecurrent=true spice_ignore=0}
C {ammeter.sym} 880 -1030 0 0 {name=v_i_buf_1 savecurrent=true spice_ignore=0}
C {lab_wire.sym} 860 -500 0 0 {name=p15 sig_type=std_logic lab=VDD}
C {ammeter.sym} 860 -470 0 0 {name=v_i_buf_2 savecurrent=true spice_ignore=0}
C {lab_wire.sym} 1790 -1310 0 0 {name=p37 sig_type=std_logic lab=v_bias_nmos
}
C {ammeter.sym} 1840 -1470 0 0 {name=v_i_tail_2 savecurrent=true spice_ignore=0}
C {lab_wire.sym} 870 -1180 0 0 {name=p40 sig_type=std_logic lab=VSS}
C {symbols/nfet_03v3.sym} 810 -1250 0 0 {name=M36
L=.5u
W=32u
nf=8
m=1
ad="'int((nf+1)/2) * W/nf * 0.18u'"
pd="'2*int((nf+1)/2) * (W/nf + 0.18u)'"
as="'int((nf+2)/2) * W/nf * 0.18u'"
ps="'2*int((nf+2)/2) * (W/nf + 0.18u)'"
nrd="'0.18u / W'" nrs="'0.18u / W'"
sa=0 sb=0 sd=0
model=nfet_03v3
spiceprefix=X
}
C {lab_wire.sym} 780 -1250 0 0 {name=p45 sig_type=std_logic lab=v_bias_nmos
}
C {ammeter.sym} 830 -1410 0 0 {name=v_i_tail_1 savecurrent=true spice_ignore=0}
C {lab_wire.sym} 910 -860 0 0 {name=p7 sig_type=std_logic lab=Va}
C {lab_wire.sym} 1520 -1580 0 0 {name=p9 sig_type=std_logic lab=LO_REF}
C {lab_wire.sym} 1010 -1580 0 0 {name=p19 sig_type=std_logic lab=LO_REF}
C {lab_wire.sym} 2140 -450 0 0 {name=p4 sig_type=std_logic lab=VDD}
C {lab_wire.sym} 2140 -180 0 0 {name=p31 sig_type=std_logic lab=VSS}
C {symbols/nfet_03v3.sym} 3160 -460 0 0 {name=M33
L=.5u
W=4u
nf=1
m=1
ad="'int((nf+1)/2) * W/nf * 0.18u'"
pd="'2*int((nf+1)/2) * (W/nf + 0.18u)'"
as="'int((nf+2)/2) * W/nf * 0.18u'"
ps="'2*int((nf+2)/2) * (W/nf + 0.18u)'"
nrd="'0.18u / W'" nrs="'0.18u / W'"
sa=0 sb=0 sd=0
model=nfet_03v3
spiceprefix=X
}
C {lab_wire.sym} 3130 -460 0 0 {name=p32 sig_type=std_logic lab=EN_BAR}
C {lab_wire.sym} 2060 -310 0 0 {name=p49 sig_type=std_logic lab=LO_REF}
